VERSION 5.8 ;
BUSBITCHARS "[]" ;
DIVIDERCHAR "/" ;
UNITS
    DATABASE MICRONS 1000 ;
END UNITS

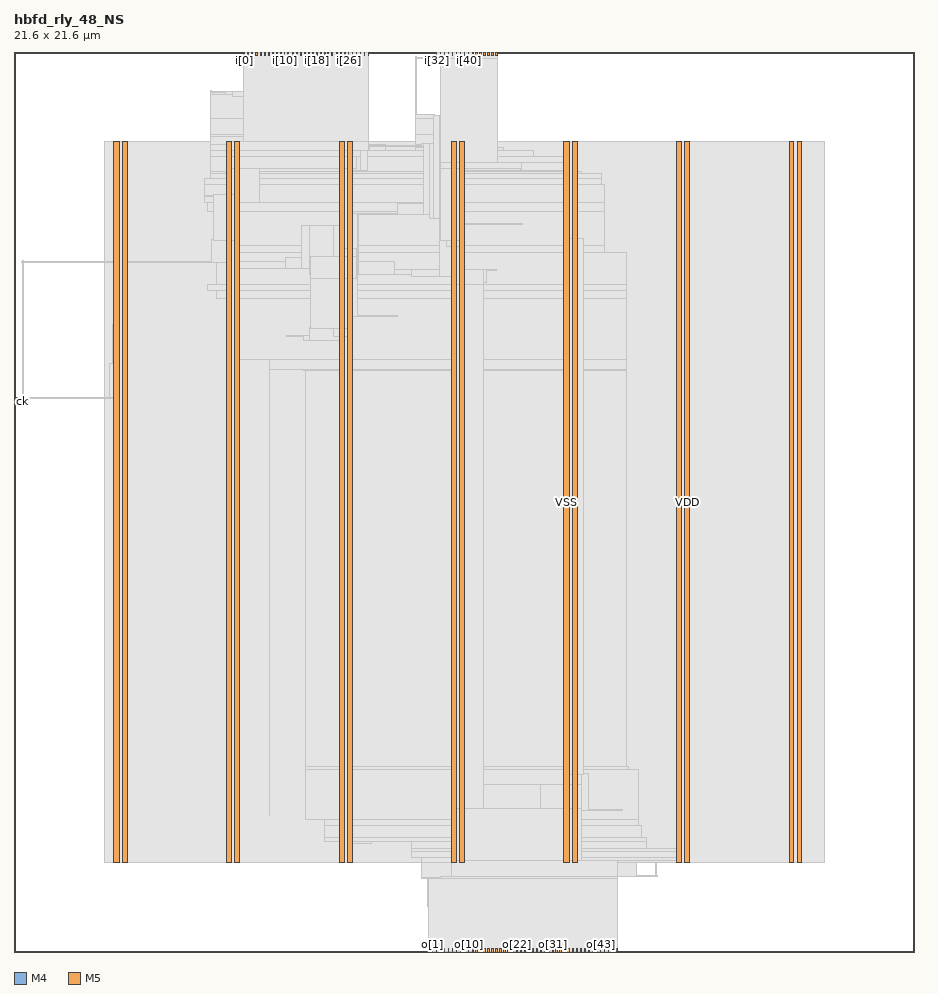
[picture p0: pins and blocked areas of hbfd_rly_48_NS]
MACRO hbfd_rly_48_NS
  FOREIGN hbfd_rly_48_NS 0 0 ;
  CLASS BLOCK ;
  SIZE 21.6 BY 21.6 ;
  PIN ck
    DIRECTION INPUT ;
    USE SIGNAL ;
    PORT
      LAYER M4 ;
        RECT  0 13.2 0.084 13.224 ;
    END
  END ck
  PIN i[0]
    DIRECTION INPUT ;
    USE SIGNAL ;
    PORT
      LAYER M5 ;
        RECT  5.52 21.516 5.544 21.6 ;
    END
  END i[0]
  PIN i[10]
    DIRECTION INPUT ;
    USE SIGNAL ;
    PORT
      LAYER M5 ;
        RECT  6.48 21.516 6.504 21.6 ;
    END
  END i[10]
  PIN i[11]
    DIRECTION INPUT ;
    USE SIGNAL ;
    PORT
      LAYER M5 ;
        RECT  6.576 21.516 6.6 21.6 ;
    END
  END i[11]
  PIN i[12]
    DIRECTION INPUT ;
    USE SIGNAL ;
    PORT
      LAYER M5 ;
        RECT  6.672 21.516 6.696 21.6 ;
    END
  END i[12]
  PIN i[13]
    DIRECTION INPUT ;
    USE SIGNAL ;
    PORT
      LAYER M5 ;
        RECT  6.768 21.516 6.792 21.6 ;
    END
  END i[13]
  PIN i[14]
    DIRECTION INPUT ;
    USE SIGNAL ;
    PORT
      LAYER M5 ;
        RECT  6.864 21.516 6.888 21.6 ;
    END
  END i[14]
  PIN i[15]
    DIRECTION INPUT ;
    USE SIGNAL ;
    PORT
      LAYER M5 ;
        RECT  6.96 21.516 6.984 21.6 ;
    END
  END i[15]
  PIN i[16]
    DIRECTION INPUT ;
    USE SIGNAL ;
    PORT
      LAYER M5 ;
        RECT  7.056 21.516 7.08 21.6 ;
    END
  END i[16]
  PIN i[17]
    DIRECTION INPUT ;
    USE SIGNAL ;
    PORT
      LAYER M5 ;
        RECT  7.152 21.516 7.176 21.6 ;
    END
  END i[17]
  PIN i[18]
    DIRECTION INPUT ;
    USE SIGNAL ;
    PORT
      LAYER M5 ;
        RECT  7.248 21.516 7.272 21.6 ;
    END
  END i[18]
  PIN i[19]
    DIRECTION INPUT ;
    USE SIGNAL ;
    PORT
      LAYER M5 ;
        RECT  7.344 21.516 7.368 21.6 ;
    END
  END i[19]
  PIN i[1]
    DIRECTION INPUT ;
    USE SIGNAL ;
    PORT
      LAYER M5 ;
        RECT  5.616 21.516 5.64 21.6 ;
    END
  END i[1]
  PIN i[20]
    DIRECTION INPUT ;
    USE SIGNAL ;
    PORT
      LAYER M5 ;
        RECT  7.44 21.516 7.464 21.6 ;
    END
  END i[20]
  PIN i[21]
    DIRECTION INPUT ;
    USE SIGNAL ;
    PORT
      LAYER M5 ;
        RECT  7.536 21.516 7.56 21.6 ;
    END
  END i[21]
  PIN i[22]
    DIRECTION INPUT ;
    USE SIGNAL ;
    PORT
      LAYER M5 ;
        RECT  7.632 21.516 7.656 21.6 ;
    END
  END i[22]
  PIN i[23]
    DIRECTION INPUT ;
    USE SIGNAL ;
    PORT
      LAYER M5 ;
        RECT  7.728 21.516 7.752 21.6 ;
    END
  END i[23]
  PIN i[24]
    DIRECTION INPUT ;
    USE SIGNAL ;
    PORT
      LAYER M5 ;
        RECT  7.824 21.516 7.848 21.6 ;
    END
  END i[24]
  PIN i[25]
    DIRECTION INPUT ;
    USE SIGNAL ;
    PORT
      LAYER M5 ;
        RECT  7.92 21.516 7.944 21.6 ;
    END
  END i[25]
  PIN i[26]
    DIRECTION INPUT ;
    USE SIGNAL ;
    PORT
      LAYER M5 ;
        RECT  8.016 21.516 8.04 21.6 ;
    END
  END i[26]
  PIN i[27]
    DIRECTION INPUT ;
    USE SIGNAL ;
    PORT
      LAYER M5 ;
        RECT  8.112 21.516 8.136 21.6 ;
    END
  END i[27]
  PIN i[28]
    DIRECTION INPUT ;
    USE SIGNAL ;
    PORT
      LAYER M5 ;
        RECT  8.208 21.516 8.232 21.6 ;
    END
  END i[28]
  PIN i[29]
    DIRECTION INPUT ;
    USE SIGNAL ;
    PORT
      LAYER M5 ;
        RECT  8.304 21.516 8.328 21.6 ;
    END
  END i[29]
  PIN i[2]
    DIRECTION INPUT ;
    USE SIGNAL ;
    PORT
      LAYER M5 ;
        RECT  5.712 21.516 5.736 21.6 ;
    END
  END i[2]
  PIN i[30]
    DIRECTION INPUT ;
    USE SIGNAL ;
    PORT
      LAYER M5 ;
        RECT  8.4 21.516 8.424 21.6 ;
    END
  END i[30]
  PIN i[31]
    DIRECTION INPUT ;
    USE SIGNAL ;
    PORT
      LAYER M5 ;
        RECT  8.496 21.516 8.52 21.6 ;
    END
  END i[31]
  PIN i[32]
    DIRECTION INPUT ;
    USE SIGNAL ;
    PORT
      LAYER M5 ;
        RECT  10.128 21.516 10.152 21.6 ;
    END
  END i[32]
  PIN i[33]
    DIRECTION INPUT ;
    USE SIGNAL ;
    PORT
      LAYER M5 ;
        RECT  10.224 21.516 10.248 21.6 ;
    END
  END i[33]
  PIN i[34]
    DIRECTION INPUT ;
    USE SIGNAL ;
    PORT
      LAYER M5 ;
        RECT  10.32 21.516 10.344 21.6 ;
    END
  END i[34]
  PIN i[35]
    DIRECTION INPUT ;
    USE SIGNAL ;
    PORT
      LAYER M5 ;
        RECT  10.416 21.516 10.44 21.6 ;
    END
  END i[35]
  PIN i[36]
    DIRECTION INPUT ;
    USE SIGNAL ;
    PORT
      LAYER M5 ;
        RECT  10.512 21.516 10.536 21.6 ;
    END
  END i[36]
  PIN i[37]
    DIRECTION INPUT ;
    USE SIGNAL ;
    PORT
      LAYER M5 ;
        RECT  10.608 21.516 10.632 21.6 ;
    END
  END i[37]
  PIN i[38]
    DIRECTION INPUT ;
    USE SIGNAL ;
    PORT
      LAYER M5 ;
        RECT  10.704 21.516 10.728 21.6 ;
    END
  END i[38]
  PIN i[39]
    DIRECTION INPUT ;
    USE SIGNAL ;
    PORT
      LAYER M5 ;
        RECT  10.8 21.516 10.824 21.6 ;
    END
  END i[39]
  PIN i[3]
    DIRECTION INPUT ;
    USE SIGNAL ;
    PORT
      LAYER M5 ;
        RECT  5.808 21.516 5.832 21.6 ;
    END
  END i[3]
  PIN i[40]
    DIRECTION INPUT ;
    USE SIGNAL ;
    PORT
      LAYER M5 ;
        RECT  10.896 21.516 10.92 21.6 ;
    END
  END i[40]
  PIN i[41]
    DIRECTION INPUT ;
    USE SIGNAL ;
    PORT
      LAYER M5 ;
        RECT  10.992 21.516 11.016 21.6 ;
    END
  END i[41]
  PIN i[42]
    DIRECTION INPUT ;
    USE SIGNAL ;
    PORT
      LAYER M5 ;
        RECT  11.088 21.516 11.112 21.6 ;
    END
  END i[42]
  PIN i[43]
    DIRECTION INPUT ;
    USE SIGNAL ;
    PORT
      LAYER M5 ;
        RECT  11.184 21.516 11.208 21.6 ;
    END
  END i[43]
  PIN i[44]
    DIRECTION INPUT ;
    USE SIGNAL ;
    PORT
      LAYER M5 ;
        RECT  11.28 21.516 11.304 21.6 ;
    END
  END i[44]
  PIN i[45]
    DIRECTION INPUT ;
    USE SIGNAL ;
    PORT
      LAYER M5 ;
        RECT  11.376 21.516 11.4 21.6 ;
    END
  END i[45]
  PIN i[46]
    DIRECTION INPUT ;
    USE SIGNAL ;
    PORT
      LAYER M5 ;
        RECT  11.472 21.516 11.496 21.6 ;
    END
  END i[46]
  PIN i[47]
    DIRECTION INPUT ;
    USE SIGNAL ;
    PORT
      LAYER M5 ;
        RECT  11.568 21.516 11.592 21.6 ;
    END
  END i[47]
  PIN i[4]
    DIRECTION INPUT ;
    USE SIGNAL ;
    PORT
      LAYER M5 ;
        RECT  5.904 21.516 5.928 21.6 ;
    END
  END i[4]
  PIN i[5]
    DIRECTION INPUT ;
    USE SIGNAL ;
    PORT
      LAYER M5 ;
        RECT  6 21.516 6.024 21.6 ;
    END
  END i[5]
  PIN i[6]
    DIRECTION INPUT ;
    USE SIGNAL ;
    PORT
      LAYER M5 ;
        RECT  6.096 21.516 6.12 21.6 ;
    END
  END i[6]
  PIN i[7]
    DIRECTION INPUT ;
    USE SIGNAL ;
    PORT
      LAYER M5 ;
        RECT  6.192 21.516 6.216 21.6 ;
    END
  END i[7]
  PIN i[8]
    DIRECTION INPUT ;
    USE SIGNAL ;
    PORT
      LAYER M5 ;
        RECT  6.288 21.516 6.312 21.6 ;
    END
  END i[8]
  PIN i[9]
    DIRECTION INPUT ;
    USE SIGNAL ;
    PORT
      LAYER M5 ;
        RECT  6.384 21.516 6.408 21.6 ;
    END
  END i[9]
  PIN o[0]
    DIRECTION OUTPUT ;
    USE SIGNAL ;
    PORT
      LAYER M5 ;
        RECT  9.936 0 9.96 0.084 ;
    END
  END o[0]
  PIN o[10]
    DIRECTION OUTPUT ;
    USE SIGNAL ;
    PORT
      LAYER M5 ;
        RECT  10.896 0 10.92 0.084 ;
    END
  END o[10]
  PIN o[11]
    DIRECTION OUTPUT ;
    USE SIGNAL ;
    PORT
      LAYER M5 ;
        RECT  10.992 0 11.016 0.084 ;
    END
  END o[11]
  PIN o[12]
    DIRECTION OUTPUT ;
    USE SIGNAL ;
    PORT
      LAYER M5 ;
        RECT  11.088 0 11.112 0.084 ;
    END
  END o[12]
  PIN o[13]
    DIRECTION OUTPUT ;
    USE SIGNAL ;
    PORT
      LAYER M5 ;
        RECT  11.184 0 11.208 0.084 ;
    END
  END o[13]
  PIN o[14]
    DIRECTION OUTPUT ;
    USE SIGNAL ;
    PORT
      LAYER M5 ;
        RECT  11.28 0 11.304 0.084 ;
    END
  END o[14]
  PIN o[15]
    DIRECTION OUTPUT ;
    USE SIGNAL ;
    PORT
      LAYER M5 ;
        RECT  11.376 0 11.4 0.084 ;
    END
  END o[15]
  PIN o[16]
    DIRECTION OUTPUT ;
    USE SIGNAL ;
    PORT
      LAYER M5 ;
        RECT  11.472 0 11.496 0.084 ;
    END
  END o[16]
  PIN o[17]
    DIRECTION OUTPUT ;
    USE SIGNAL ;
    PORT
      LAYER M5 ;
        RECT  11.568 0 11.592 0.084 ;
    END
  END o[17]
  PIN o[18]
    DIRECTION OUTPUT ;
    USE SIGNAL ;
    PORT
      LAYER M5 ;
        RECT  11.664 0 11.688 0.084 ;
    END
  END o[18]
  PIN o[19]
    DIRECTION OUTPUT ;
    USE SIGNAL ;
    PORT
      LAYER M5 ;
        RECT  11.76 0 11.784 0.084 ;
    END
  END o[19]
  PIN o[1]
    DIRECTION OUTPUT ;
    USE SIGNAL ;
    PORT
      LAYER M5 ;
        RECT  10.032 0 10.056 0.084 ;
    END
  END o[1]
  PIN o[20]
    DIRECTION OUTPUT ;
    USE SIGNAL ;
    PORT
      LAYER M5 ;
        RECT  11.856 0 11.88 0.084 ;
    END
  END o[20]
  PIN o[21]
    DIRECTION OUTPUT ;
    USE SIGNAL ;
    PORT
      LAYER M5 ;
        RECT  11.952 0 11.976 0.084 ;
    END
  END o[21]
  PIN o[22]
    DIRECTION OUTPUT ;
    USE SIGNAL ;
    PORT
      LAYER M5 ;
        RECT  12.048 0 12.072 0.084 ;
    END
  END o[22]
  PIN o[23]
    DIRECTION OUTPUT ;
    USE SIGNAL ;
    PORT
      LAYER M5 ;
        RECT  12.144 0 12.168 0.084 ;
    END
  END o[23]
  PIN o[24]
    DIRECTION OUTPUT ;
    USE SIGNAL ;
    PORT
      LAYER M5 ;
        RECT  12.24 0 12.264 0.084 ;
    END
  END o[24]
  PIN o[25]
    DIRECTION OUTPUT ;
    USE SIGNAL ;
    PORT
      LAYER M5 ;
        RECT  12.336 0 12.36 0.084 ;
    END
  END o[25]
  PIN o[26]
    DIRECTION OUTPUT ;
    USE SIGNAL ;
    PORT
      LAYER M5 ;
        RECT  12.432 0 12.456 0.084 ;
    END
  END o[26]
  PIN o[27]
    DIRECTION OUTPUT ;
    USE SIGNAL ;
    PORT
      LAYER M5 ;
        RECT  12.528 0 12.552 0.084 ;
    END
  END o[27]
  PIN o[28]
    DIRECTION OUTPUT ;
    USE SIGNAL ;
    PORT
      LAYER M5 ;
        RECT  12.624 0 12.648 0.084 ;
    END
  END o[28]
  PIN o[29]
    DIRECTION OUTPUT ;
    USE SIGNAL ;
    PORT
      LAYER M5 ;
        RECT  12.72 0 12.744 0.084 ;
    END
  END o[29]
  PIN o[2]
    DIRECTION OUTPUT ;
    USE SIGNAL ;
    PORT
      LAYER M5 ;
        RECT  10.128 0 10.152 0.084 ;
    END
  END o[2]
  PIN o[30]
    DIRECTION OUTPUT ;
    USE SIGNAL ;
    PORT
      LAYER M5 ;
        RECT  12.816 0 12.84 0.084 ;
    END
  END o[30]
  PIN o[31]
    DIRECTION OUTPUT ;
    USE SIGNAL ;
    PORT
      LAYER M5 ;
        RECT  12.912 0 12.936 0.084 ;
    END
  END o[31]
  PIN o[32]
    DIRECTION OUTPUT ;
    USE SIGNAL ;
    PORT
      LAYER M5 ;
        RECT  13.008 0 13.032 0.084 ;
    END
  END o[32]
  PIN o[33]
    DIRECTION OUTPUT ;
    USE SIGNAL ;
    PORT
      LAYER M5 ;
        RECT  13.104 0 13.128 0.084 ;
    END
  END o[33]
  PIN o[34]
    DIRECTION OUTPUT ;
    USE SIGNAL ;
    PORT
      LAYER M5 ;
        RECT  13.2 0 13.224 0.084 ;
    END
  END o[34]
  PIN o[35]
    DIRECTION OUTPUT ;
    USE SIGNAL ;
    PORT
      LAYER M5 ;
        RECT  13.296 0 13.32 0.084 ;
    END
  END o[35]
  PIN o[36]
    DIRECTION OUTPUT ;
    USE SIGNAL ;
    PORT
      LAYER M5 ;
        RECT  13.392 0 13.416 0.084 ;
    END
  END o[36]
  PIN o[37]
    DIRECTION OUTPUT ;
    USE SIGNAL ;
    PORT
      LAYER M5 ;
        RECT  13.488 0 13.512 0.084 ;
    END
  END o[37]
  PIN o[38]
    DIRECTION OUTPUT ;
    USE SIGNAL ;
    PORT
      LAYER M5 ;
        RECT  13.584 0 13.608 0.084 ;
    END
  END o[38]
  PIN o[39]
    DIRECTION OUTPUT ;
    USE SIGNAL ;
    PORT
      LAYER M5 ;
        RECT  13.68 0 13.704 0.084 ;
    END
  END o[39]
  PIN o[3]
    DIRECTION OUTPUT ;
    USE SIGNAL ;
    PORT
      LAYER M5 ;
        RECT  10.224 0 10.248 0.084 ;
    END
  END o[3]
  PIN o[40]
    DIRECTION OUTPUT ;
    USE SIGNAL ;
    PORT
      LAYER M5 ;
        RECT  13.776 0 13.8 0.084 ;
    END
  END o[40]
  PIN o[41]
    DIRECTION OUTPUT ;
    USE SIGNAL ;
    PORT
      LAYER M5 ;
        RECT  13.872 0 13.896 0.084 ;
    END
  END o[41]
  PIN o[42]
    DIRECTION OUTPUT ;
    USE SIGNAL ;
    PORT
      LAYER M5 ;
        RECT  13.968 0 13.992 0.084 ;
    END
  END o[42]
  PIN o[43]
    DIRECTION OUTPUT ;
    USE SIGNAL ;
    PORT
      LAYER M5 ;
        RECT  14.064 0 14.088 0.084 ;
    END
  END o[43]
  PIN o[44]
    DIRECTION OUTPUT ;
    USE SIGNAL ;
    PORT
      LAYER M5 ;
        RECT  14.16 0 14.184 0.084 ;
    END
  END o[44]
  PIN o[45]
    DIRECTION OUTPUT ;
    USE SIGNAL ;
    PORT
      LAYER M5 ;
        RECT  14.256 0 14.28 0.084 ;
    END
  END o[45]
  PIN o[46]
    DIRECTION OUTPUT ;
    USE SIGNAL ;
    PORT
      LAYER M5 ;
        RECT  14.352 0 14.376 0.084 ;
    END
  END o[46]
  PIN o[47]
    DIRECTION OUTPUT ;
    USE SIGNAL ;
    PORT
      LAYER M5 ;
        RECT  14.448 0 14.472 0.084 ;
    END
  END o[47]
  PIN o[4]
    DIRECTION OUTPUT ;
    USE SIGNAL ;
    PORT
      LAYER M5 ;
        RECT  10.32 0 10.344 0.084 ;
    END
  END o[4]
  PIN o[5]
    DIRECTION OUTPUT ;
    USE SIGNAL ;
    PORT
      LAYER M5 ;
        RECT  10.416 0 10.44 0.084 ;
    END
  END o[5]
  PIN o[6]
    DIRECTION OUTPUT ;
    USE SIGNAL ;
    PORT
      LAYER M5 ;
        RECT  10.512 0 10.536 0.084 ;
    END
  END o[6]
  PIN o[7]
    DIRECTION OUTPUT ;
    USE SIGNAL ;
    PORT
      LAYER M5 ;
        RECT  10.608 0 10.632 0.084 ;
    END
  END o[7]
  PIN o[8]
    DIRECTION OUTPUT ;
    USE SIGNAL ;
    PORT
      LAYER M5 ;
        RECT  10.704 0 10.728 0.084 ;
    END
  END o[8]
  PIN o[9]
    DIRECTION OUTPUT ;
    USE SIGNAL ;
    PORT
      LAYER M5 ;
        RECT  10.8 0 10.824 0.084 ;
    END
  END o[9]
  PIN rs
    DIRECTION INPUT ;
    USE SIGNAL ;
    PORT
      LAYER M4 ;
        RECT  0 13.296 0.084 13.32 ;
    END
  END rs
  PIN VDD
    DIRECTION INOUT ;
    USE POWER ;
    PORT
      LAYER M5 ;
        RECT  18.792 2.151 18.912 19.449 ;
        RECT  16.092 2.151 16.212 19.449 ;
        RECT  13.392 2.151 13.512 19.449 ;
        RECT  10.692 2.151 10.812 19.449 ;
        RECT  7.992 2.151 8.112 19.449 ;
        RECT  5.292 2.151 5.412 19.449 ;
        RECT  2.592 2.151 2.712 19.449 ;
    END
  END VDD
  PIN VSS
    DIRECTION INOUT ;
    USE GROUND ;
    PORT
      LAYER M5 ;
        RECT  18.6 2.137 18.72 19.463 ;
        RECT  15.9 2.137 16.02 19.463 ;
        RECT  13.2 2.137 13.32 19.463 ;
        RECT  10.5 2.137 10.62 19.463 ;
        RECT  7.8 2.137 7.92 19.463 ;
        RECT  5.1 2.137 5.22 19.463 ;
        RECT  2.4 2.137 2.52 19.463 ;
    END
  END VSS
  # OT_OBS_CLOSED layer=M5 d_um=1.536 added=4
  OBS
    LAYER RVTN ;
     RECT  2.16 2.16 19.44 2.295 ;
     RECT  2.16 2.565 19.44 2.835 ;
     RECT  2.16 3.105 19.44 3.375 ;
     RECT  2.16 3.645 19.44 3.915 ;
     RECT  2.16 4.185 19.44 4.455 ;
     RECT  2.16 4.725 19.44 4.995 ;
     RECT  2.16 5.265 19.44 5.535 ;
     RECT  2.16 5.805 19.44 6.075 ;
     RECT  2.16 6.345 19.44 6.615 ;
     RECT  2.16 6.885 19.44 7.155 ;
     RECT  2.16 7.425 19.44 7.695 ;
     RECT  2.16 7.965 19.44 8.235 ;
     RECT  2.16 8.505 19.44 8.775 ;
     RECT  2.16 9.045 19.44 9.315 ;
     RECT  2.16 9.585 19.44 9.855 ;
     RECT  2.16 10.125 19.44 10.395 ;
     RECT  2.16 10.665 19.44 10.935 ;
     RECT  2.16 11.205 19.44 11.475 ;
     RECT  2.16 11.745 19.44 12.015 ;
     RECT  2.16 12.285 19.44 12.555 ;
     RECT  2.16 12.825 19.44 13.095 ;
     RECT  2.16 13.365 19.44 13.635 ;
     RECT  2.16 13.905 19.44 14.175 ;
     RECT  2.16 14.445 19.44 14.715 ;
     RECT  2.16 14.985 19.44 15.255 ;
     RECT  2.16 15.525 19.44 15.795 ;
     RECT  2.16 16.065 19.44 16.335 ;
     RECT  2.16 16.605 19.44 16.875 ;
     RECT  2.16 17.145 19.44 17.415 ;
     RECT  2.16 17.685 19.44 17.955 ;
     RECT  2.16 18.225 19.44 18.495 ;
     RECT  2.16 18.765 19.44 19.035 ;
     RECT  2.16 19.305 19.44 19.44 ;
    LAYER RVTP ;
     RECT  2.16 2.295 19.44 2.565 ;
     RECT  2.16 2.835 19.44 3.105 ;
     RECT  2.16 3.375 19.44 3.645 ;
     RECT  2.16 3.915 19.44 4.185 ;
     RECT  2.16 4.455 19.44 4.725 ;
     RECT  2.16 4.995 19.44 5.265 ;
     RECT  2.16 5.535 19.44 5.805 ;
     RECT  2.16 6.075 19.44 6.345 ;
     RECT  2.16 6.615 19.44 6.885 ;
     RECT  2.16 7.155 19.44 7.425 ;
     RECT  2.16 7.695 19.44 7.965 ;
     RECT  2.16 8.235 19.44 8.505 ;
     RECT  2.16 8.775 19.44 9.045 ;
     RECT  2.16 9.315 19.44 9.585 ;
     RECT  2.16 9.855 19.44 10.125 ;
     RECT  2.16 10.395 19.44 10.665 ;
     RECT  2.16 10.935 19.44 11.205 ;
     RECT  2.16 11.475 19.44 11.745 ;
     RECT  2.16 12.015 19.44 12.285 ;
     RECT  2.16 12.555 19.44 12.825 ;
     RECT  2.16 13.095 19.44 13.365 ;
     RECT  2.16 13.635 19.44 13.905 ;
     RECT  2.16 14.175 19.44 14.445 ;
     RECT  2.16 14.715 19.44 14.985 ;
     RECT  2.16 15.255 19.44 15.525 ;
     RECT  2.16 15.795 19.44 16.065 ;
     RECT  2.16 16.335 19.44 16.605 ;
     RECT  2.16 16.875 19.44 17.145 ;
     RECT  2.16 17.415 19.44 17.685 ;
     RECT  2.16 17.955 19.44 18.225 ;
     RECT  2.16 18.495 19.44 18.765 ;
     RECT  2.16 19.035 19.44 19.305 ;
    LAYER M1 ;
     RECT  2.16 2.151 19.44 19.449 ;
    LAYER M2 ;
     RECT  2.16 2.151 19.44 19.449 ;
    LAYER M3 ;
     RECT  10.368 0.091 10.386 0.139 ;
     RECT  14.04 0.091 14.058 0.187 ;
     RECT  11.376 0.091 12.978 0.523 ;
     RECT  14.04 0.187 14.094 0.523 ;
     RECT  10.368 0.139 10.494 0.571 ;
     RECT  11.376 0.523 14.094 0.571 ;
     RECT  10.152 0.571 10.494 1.099 ;
     RECT  11.232 0.571 14.382 1.099 ;
     RECT  9.936 1.099 14.382 1.723 ;
     RECT  9.936 1.723 14.418 1.771 ;
     RECT  15.408 1.819 15.426 2.143 ;
     RECT  9.792 1.771 14.418 2.155 ;
     RECT  15.408 2.143 16.005 2.155 ;
     RECT  9.792 2.155 16.005 2.263 ;
     RECT  2.415 2.143 2.505 2.413 ;
     RECT  5.115 2.143 5.205 2.413 ;
     RECT  7.815 2.143 7.905 2.413 ;
     RECT  9.54 2.263 16.005 2.413 ;
     RECT  18.615 2.143 18.705 2.413 ;
     RECT  9.54 2.413 16.197 2.489 ;
     RECT  7.815 2.413 8.097 2.605 ;
     RECT  7.815 2.605 8.586 2.641 ;
     RECT  9.54 2.489 15.174 2.641 ;
     RECT  7.452 2.641 15.174 2.759 ;
     RECT  7.452 2.759 15.066 3.029 ;
     RECT  7.452 3.029 14.994 3.181 ;
     RECT  6.984 3.181 14.994 4.379 ;
     RECT  6.984 4.379 14.742 4.451 ;
     RECT  2.415 2.413 2.697 13.291 ;
     RECT  6.984 4.451 14.706 13.945 ;
     RECT  6.12 3.271 6.138 13.981 ;
     RECT  6.948 13.945 14.706 13.981 ;
     RECT  2.304 13.291 2.697 14.135 ;
     RECT  5.115 2.413 5.397 14.215 ;
     RECT  6.12 13.981 14.706 14.215 ;
     RECT  2.376 14.135 2.697 15.053 ;
     RECT  5.115 14.215 14.706 15.691 ;
     RECT  4.86 15.691 14.706 15.871 ;
     RECT  4.644 15.871 14.706 16.025 ;
     RECT  4.86 16.025 14.706 16.799 ;
     RECT  4.86 16.799 14.166 16.951 ;
     RECT  4.788 16.951 14.166 17.761 ;
     RECT  4.644 17.761 14.166 17.995 ;
     RECT  4.572 17.995 14.166 18.419 ;
     RECT  4.572 18.419 14.094 18.563 ;
     RECT  4.716 18.563 14.094 18.689 ;
     RECT  4.716 18.689 13.626 18.725 ;
     RECT  4.716 18.725 13.497 19.103 ;
     RECT  2.415 15.053 2.697 19.187 ;
     RECT  13.215 19.103 13.497 19.187 ;
     RECT  15.915 2.489 16.197 19.187 ;
     RECT  18.615 2.413 18.897 19.187 ;
     RECT  4.716 19.103 12.474 19.229 ;
     RECT  9.648 19.229 11.754 19.301 ;
     RECT  4.716 19.229 8.91 19.373 ;
     RECT  9.648 19.301 11.394 19.373 ;
     RECT  2.415 19.187 2.505 19.457 ;
     RECT  13.215 19.187 13.305 19.457 ;
     RECT  15.915 19.187 16.005 19.457 ;
     RECT  18.615 19.187 18.705 19.457 ;
     RECT  4.716 19.373 8.298 19.565 ;
     RECT  4.716 19.565 7.974 19.613 ;
     RECT  9.648 19.373 11.178 19.613 ;
     RECT  4.716 19.613 7.758 19.997 ;
     RECT  9.648 19.613 10.134 19.997 ;
     RECT  9.648 19.997 10.098 20.093 ;
     RECT  4.716 19.997 6.174 20.573 ;
     RECT  7.308 19.997 7.758 20.573 ;
     RECT  4.716 20.573 5.094 20.621 ;
     RECT  6.156 20.573 6.174 20.621 ;
     RECT  4.716 20.621 4.734 20.669 ;
     RECT  9.648 20.093 9.666 21.485 ;
     RECT  11.16 19.613 11.178 21.485 ;
    LAYER M4 ;
     RECT  0.06 13.2 0.227 13.32 ;
     RECT  0.227 13.296 2.408 13.32 ;
     RECT  0.181 16.56 2.408 16.584 ;
     RECT  2.408 2.148 2.512 19.452 ;
     RECT  2.512 2.418 2.704 19.182 ;
     RECT  2.704 16.56 4.748 16.584 ;
     RECT  4.705 20.64 5.065 20.664 ;
     RECT  4.748 16.56 5.108 17.112 ;
     RECT  4.561 18.144 5.108 18.168 ;
     RECT  5.108 2.148 5.212 19.452 ;
     RECT  5.065 20.592 5.245 20.664 ;
     RECT  5.212 2.418 5.404 19.416 ;
     RECT  5.404 18 5.897 19.416 ;
     RECT  5.245 20.544 6.035 20.664 ;
     RECT  6.035 20.544 6.419 20.616 ;
     RECT  5.404 16.416 6.505 16.584 ;
     RECT  5.897 18.816 6.577 19.416 ;
     RECT  6.419 20.544 6.577 20.568 ;
     RECT  6.505 16.416 6.901 16.68 ;
     RECT  6.541 14.784 6.937 14.808 ;
     RECT  6.937 14.688 7.093 14.808 ;
     RECT  6.901 16.416 7.093 17.448 ;
     RECT  7.093 16.272 7.669 17.448 ;
     RECT  7.093 14.688 7.808 15 ;
     RECT  7.669 15.984 7.808 17.448 ;
     RECT  6.577 18.816 7.808 20.568 ;
     RECT  7.808 2.148 7.912 20.568 ;
     RECT  7.912 2.418 7.996 20.568 ;
     RECT  7.996 20.544 8.051 20.568 ;
     RECT  7.996 2.418 8.104 19.56 ;
     RECT  8.104 15.264 8.243 17.736 ;
     RECT  8.243 16.272 8.273 17.736 ;
     RECT  8.104 18.768 8.309 19.56 ;
     RECT  8.309 18.768 8.489 19.368 ;
     RECT  8.489 19.248 8.531 19.368 ;
     RECT  8.273 16.272 9.137 16.584 ;
     RECT  8.273 17.712 9.205 17.736 ;
     RECT  8.243 15.264 9.209 15.288 ;
     RECT  9.137 16.272 9.529 16.392 ;
     RECT  8.531 19.344 9.781 19.368 ;
     RECT  9.205 17.712 9.817 17.976 ;
     RECT  9.781 19.344 9.817 19.416 ;
     RECT  9.781 1.776 9.925 1.8 ;
     RECT  9.817 17.712 9.961 19.416 ;
     RECT  9.961 17.616 10.069 19.416 ;
     RECT  9.925 1.104 10.097 1.8 ;
     RECT  9.637 21.456 10.163 21.48 ;
     RECT  9.529 16.224 10.205 16.392 ;
     RECT  10.069 17.616 10.205 20.088 ;
     RECT  10.097 0.576 10.309 1.8 ;
     RECT  10.309 0.096 10.508 1.8 ;
     RECT  10.205 16.224 10.508 20.088 ;
     RECT  10.357 21.408 10.739 21.432 ;
     RECT  10.508 0.096 10.804 20.088 ;
     RECT  10.804 18.816 10.835 20.088 ;
     RECT  10.835 18.816 10.931 19.416 ;
     RECT  10.804 0.096 11.027 3.432 ;
     RECT  10.804 14.832 11.197 14.856 ;
     RECT  11.027 0.096 11.261 0.6 ;
     RECT  10.804 15.984 11.267 16.392 ;
     RECT  11.267 16.08 11.333 16.392 ;
     RECT  10.931 18.816 11.405 19.368 ;
     RECT  11.405 18.816 11.413 19.272 ;
     RECT  11.149 21.456 11.507 21.48 ;
     RECT  11.333 16.368 11.585 16.392 ;
     RECT  11.413 18.816 11.603 19.128 ;
     RECT  11.603 18.816 12.113 18.936 ;
     RECT  12.113 18.768 12.179 18.936 ;
     RECT  10.804 17.472 12.197 17.496 ;
     RECT  12.179 18.768 12.197 18.792 ;
     RECT  11.027 1.728 12.613 3.432 ;
     RECT  12.613 1.728 13.208 4.008 ;
     RECT  11.261 0.096 13.285 0.12 ;
     RECT  13.208 1.728 13.312 19.452 ;
     RECT  13.312 1.728 13.504 19.182 ;
     RECT  13.504 17.088 13.673 17.112 ;
     RECT  13.504 3.408 13.781 4.296 ;
     RECT  13.285 0.096 14.069 0.6 ;
     RECT  14.069 0.192 14.105 0.6 ;
     RECT  14.105 0.576 14.393 0.6 ;
     RECT  13.504 1.728 14.429 2.184 ;
     RECT  13.781 3.408 14.609 3.432 ;
     RECT  14.429 1.824 14.933 2.184 ;
     RECT  14.933 1.824 15.437 1.848 ;
     RECT  15.908 2.148 16.012 19.452 ;
     RECT  16.012 2.418 16.204 19.182 ;
     RECT  18.608 2.148 18.712 19.452 ;
     RECT  18.712 2.418 18.904 19.182 ;
    LAYER M5 ;
     RECT  9.936 0.016 14.472 1.763 ;
     RECT  10.224 1.763 14.472 1.811 ;
     RECT  2.4 2.137 2.52 2.151 ;
     RECT  5.1 2.137 5.22 2.151 ;
     RECT  7.8 2.137 7.92 2.151 ;
     RECT  15.9 2.137 16.02 2.151 ;
     RECT  18.6 2.137 18.72 2.151 ;
     RECT  10.5 1.811 14.472 2.195 ;
     RECT  10.5 2.195 13.608 3.443 ;
     RECT  12.624 3.443 13.608 4.019 ;
     RECT  13.2 4.019 13.608 4.261 ;
     RECT  7.8 2.151 8.112 14.773 ;
     RECT  7.68 14.773 8.112 14.965 ;
     RECT  10.5 3.443 11.256 16.019 ;
     RECT  7.104 14.965 8.112 16.165 ;
     RECT  0.192 13.189 0.216 16.595 ;
     RECT  7.104 16.165 8.232 16.691 ;
     RECT  7.8 16.691 8.232 16.883 ;
     RECT  10.5 16.019 10.812 16.933 ;
     RECT  5.1 2.151 5.412 17.077 ;
     RECT  10.368 16.933 10.812 17.077 ;
     RECT  13.2 4.261 13.656 17.123 ;
     RECT  4.8 17.077 5.412 18.179 ;
     RECT  5.1 18.179 5.412 18.805 ;
     RECT  7.8 16.883 8.112 18.805 ;
     RECT  10.224 17.077 10.812 18.805 ;
     RECT  12.144 18.757 12.168 18.805 ;
     RECT  10.224 18.805 12.168 18.947 ;
     RECT  5.1 18.805 8.232 19.093 ;
     RECT  5.1 19.093 8.328 19.237 ;
     RECT  2.4 2.151 2.712 19.449 ;
     RECT  13.2 17.123 13.512 19.449 ;
     RECT  15.9 2.151 16.212 19.449 ;
     RECT  18.6 2.151 18.912 19.449 ;
     RECT  2.4 19.449 2.52 19.463 ;
     RECT  5.1 19.237 8.52 19.463 ;
     RECT  13.2 19.449 13.32 19.463 ;
     RECT  15.9 19.449 16.02 19.463 ;
     RECT  18.6 19.449 18.72 19.463 ;
     RECT  10.224 18.947 11.592 21.445 ;
     RECT  5.52 19.463 8.52 21.584 ;
     RECT  10.128 21.445 11.592 21.584 ;
     RECT  14.472 2.137 15.9 2.195 ;
     RECT  11.256 3.443 12.624 4.019 ;
     RECT  10.812 18.757 12.144 18.805 ;
     RECT  12.168 18.757 13.2 18.947 ;
  END
END hbfd_rly_48_NS
END LIBRARY
